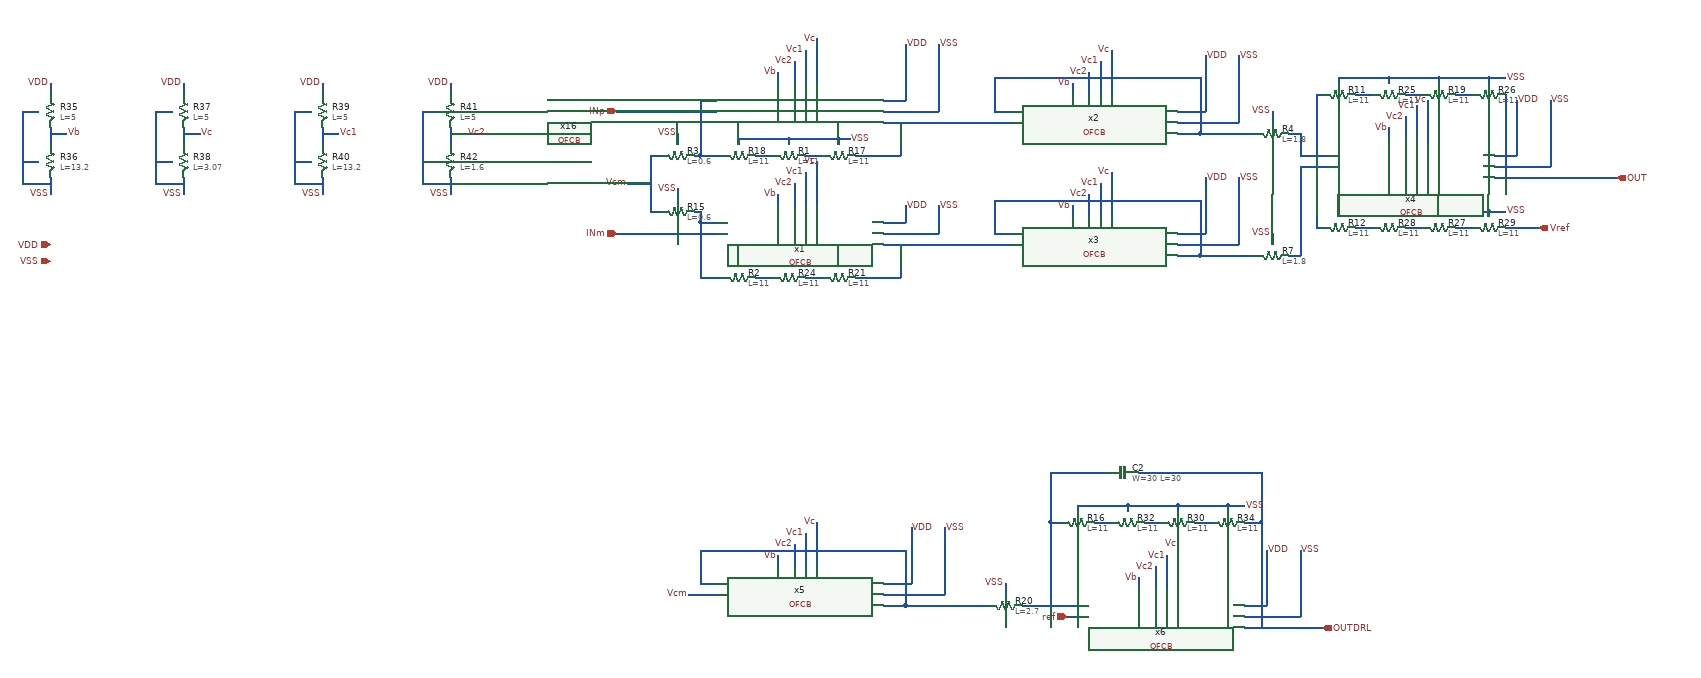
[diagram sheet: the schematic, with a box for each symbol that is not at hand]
v {xschem version=3.4.5 file_version=1.2
}
G {}
K {}
V {}
S {}
E {}
N -280 -930 -200 -930 {
lab=#net1}
N -280 -710 -200 -710 {
lab=#net2}
N 480 -850 520 -850 {
lab=#net3}
N 480 -870 520 -870 {
lab=#net4}
N -280 -970 -240 -970 {
lab=VDD}
N -240 -1070 -240 -970 {
lab=VDD}
N -280 -950 -200 -950 {
lab=VSS}
N -200 -950 -180 -950 {
lab=VSS}
N -180 -1070 -180 -950 {
lab=VSS}
N -280 -750 -240 -750 {
lab=VDD}
N -240 -780 -240 -750 {
lab=VDD}
N -280 -730 -180 -730 {
lab=VSS}
N -180 -780 -180 -730 {
lab=VSS}
N -680 -950 -580 -950 {
lab=INp}
N -680 -730 -580 -730 {
lab=INm}
N -610 -970 -580 -970 {
lab=#net5}
N -610 -970 -610 -910 {
lab=#net5}
N -250 -930 -250 -910 {
lab=#net1}
N -610 -750 -580 -750 {
lab=#net6}
N -610 -750 -610 -700 {
lab=#net6}
N -610 -700 -610 -690 {
lab=#net6}
N 820 -870 860 -870 {
lab=VDD}
N 860 -970 860 -870 {
lab=VDD}
N 820 -850 900 -850 {
lab=VSS}
N 900 -850 920 -850 {
lab=VSS}
N 920 -970 920 -850 {
lab=VSS}
N 820 -830 960 -830 {
lab=OUT}
N -250 -910 -250 -890 {
lab=#net1}
N -250 -710 -250 -690 {
lab=#net2}
N -250 -690 -250 -670 {
lab=#net2}
N 960 -830 1010 -830 {
lab=OUT}
N 1010 -830 1040 -830 {
lab=OUT}
N -610 -910 -610 -890 {
lab=#net5}
N -610 -690 -610 -670 {
lab=#net6}
N -200 -930 -190 -930 {
lab=#net1}
N -200 -710 -190 -710 {
lab=#net2}
N 500 -850 500 -740 {
lab=#net3}
N 500 -980 500 -870 {
lab=#net4}
N 840 -980 840 -830 {
lab=OUT}
N -190 -930 -50 -930 {
lab=#net1}
N -190 -710 -50 -710 {
lab=#net2}
N -80 -950 -50 -950 {
lab=#net7}
N -80 -1000 -80 -950 {
lab=#net7}
N -80 -1010 290 -1010 {
lab=#net7}
N 290 -1000 290 -910 {
lab=#net7}
N 250 -910 290 -910 {
lab=#net7}
N -80 -730 -50 -730 {
lab=#net8}
N -80 -780 -80 -730 {
lab=#net8}
N -80 -790 290 -790 {
lab=#net8}
N 290 -780 290 -690 {
lab=#net8}
N 250 -690 290 -690 {
lab=#net8}
N 260 -950 300 -950 {
lab=VDD}
N 300 -1050 300 -950 {
lab=VDD}
N 260 -930 340 -930 {
lab=VSS}
N 340 -930 360 -930 {
lab=VSS}
N 360 -1050 360 -930 {
lab=VSS}
N 250 -950 260 -950 {
lab=VDD}
N 250 -930 260 -930 {
lab=VSS}
N 260 -730 300 -730 {
lab=VDD}
N 300 -830 300 -730 {
lab=VDD}
N 260 -710 340 -710 {
lab=VSS}
N 340 -710 360 -710 {
lab=VSS}
N 360 -830 360 -710 {
lab=VSS}
N 250 -730 260 -730 {
lab=VDD}
N 250 -710 260 -710 {
lab=VSS}
N 470 -910 470 -870 {
lab=#net4}
N 470 -870 480 -870 {
lab=#net4}
N 470 -850 480 -850 {
lab=#net3}
N 470 -850 470 -690 {
lab=#net3}
N 290 -910 390 -910 {
lab=#net7}
N 450 -910 470 -910 {
lab=#net4}
N 450 -690 470 -690 {
lab=#net3}
N 290 -690 390 -690 {
lab=#net8}
N -250 -890 -250 -870 {
lab=#net1}
N -250 -670 -250 -650 {
lab=#net2}
N -610 -770 -610 -750 {
lab=#net6}
N -620 -770 -610 -770 {
lab=#net6}
N -620 -870 -610 -870 {
lab=#net5}
N -610 -890 -610 -870 {
lab=#net5}
N -700 -870 -680 -870 {
lab=Vcm}
N -700 -870 -700 -770 {
lab=Vcm}
N -700 -770 -680 -770 {
lab=Vcm}
N -760 -950 -680 -950 {
lab=INp}
N -760 -730 -680 -730 {
lab=INm}
N -740 -820 -700 -820 {
lab=Vcm}
N 370 -60 410 -60 {
lab=VDD}
N 410 -160 410 -60 {
lab=VDD}
N 370 -40 450 -40 {
lab=GND}
N 450 -40 470 -40 {
lab=GND}
N 470 -160 470 -40 {
lab=GND}
N 370 -20 510 -20 {
lab=OUTDRL}
N 400 -150 400 -20 {
lab=OUTDRL}
N 50 -40 70 -40 {
lab=ref}
N -30 -60 70 -60 {
lab=#net9}
N 20 -150 20 -60 {
lab=#net9}
N -140 -60 -90 -60 {
lab=#net10}
N 400 -210 400 -150 {
lab=OUTDRL}
N 20 -210 20 -150 {
lab=#net9}
N -610 -100 -580 -100 {
lab=#net10}
N -610 -150 -610 -100 {
lab=#net10}
N -610 -160 -240 -160 {
lab=#net10}
N -240 -150 -240 -60 {
lab=#net10}
N -280 -60 -240 -60 {
lab=#net10}
N -270 -100 -230 -100 {
lab=VDD}
N -230 -200 -230 -100 {
lab=VDD}
N -270 -80 -190 -80 {
lab=VSS}
N -190 -80 -170 -80 {
lab=VSS}
N -170 -200 -170 -80 {
lab=VSS}
N -280 -100 -270 -100 {
lab=VDD}
N -280 -80 -270 -80 {
lab=VSS}
N -240 -60 -140 -60 {
lab=#net10}
N -630 -80 -580 -80 {
lab=Vcm}
N -650 -910 -650 -890 {
lab=VSS}
N -650 -810 -650 -790 {
lab=VSS}
N -60 -100 -60 -80 {
lab=VSS}
N -610 -870 -570 -870 {
lab=#net5}
N -510 -870 -480 -870 {
lab=#net11}
N -420 -870 -390 -870 {
lab=#net12}
N -330 -870 -250 -870 {
lab=#net1}
N -540 -900 -540 -890 {
lab=VSS}
N -540 -900 -450 -900 {
lab=VSS}
N -450 -900 -450 -890 {
lab=VSS}
N -450 -900 -450 -890 {
lab=VSS}
N -450 -900 -360 -900 {
lab=VSS}
N -360 -900 -360 -890 {
lab=VSS}
N -360 -900 -340 -900 {
lab=VSS}
N -610 -650 -570 -650 {
lab=#net6}
N -510 -650 -480 -650 {
lab=#net13}
N -420 -650 -390 -650 {
lab=#net14}
N -330 -650 -250 -650 {
lab=#net2}
N -540 -680 -540 -670 {
lab=VSS}
N -540 -680 -450 -680 {
lab=VSS}
N -450 -680 -450 -670 {
lab=VSS}
N -450 -680 -450 -670 {
lab=VSS}
N -450 -680 -360 -680 {
lab=VSS}
N -360 -680 -360 -670 {
lab=VSS}
N -360 -680 -340 -680 {
lab=VSS}
N -610 -660 -610 -650 {
lab=#net6}
N -610 -670 -610 -660 {
lab=#net6}
N 420 -950 420 -930 {
lab=VSS}
N 420 -730 420 -710 {
lab=VSS}
N 570 -980 600 -980 {
lab=#net15}
N 660 -980 690 -980 {
lab=#net16}
N 540 -1010 540 -1000 {
lab=VSS}
N 540 -1010 630 -1010 {
lab=VSS}
N 630 -1010 630 -1000 {
lab=VSS}
N 630 -1010 630 -1000 {
lab=VSS}
N 630 -1010 720 -1010 {
lab=VSS}
N 720 -1010 720 -1000 {
lab=VSS}
N 720 -1010 740 -1010 {
lab=VSS}
N 500 -980 510 -980 {
lab=#net4}
N 750 -980 780 -980 {
lab=#net17}
N 810 -1010 810 -1000 {
lab=VSS}
N 740 -1010 810 -1010 {
lab=VSS}
N 810 -1010 840 -1010 {
lab=VSS}
N 570 -740 600 -740 {
lab=#net18}
N 660 -740 690 -740 {
lab=#net19}
N 540 -770 540 -760 {
lab=VSS}
N 540 -770 630 -770 {
lab=VSS}
N 630 -770 630 -760 {
lab=VSS}
N 630 -770 630 -760 {
lab=VSS}
N 630 -770 720 -770 {
lab=VSS}
N 720 -770 720 -760 {
lab=VSS}
N 720 -770 740 -770 {
lab=VSS}
N 500 -740 510 -740 {
lab=#net3}
N 750 -740 780 -740 {
lab=#net20}
N 810 -770 810 -760 {
lab=VSS}
N 740 -770 810 -770 {
lab=VSS}
N 810 -770 840 -770 {
lab=VSS}
N 840 -740 900 -740 {
lab=Vref}
N 100 -210 130 -210 {
lab=#net21}
N 190 -210 220 -210 {
lab=#net22}
N 70 -240 70 -230 {
lab=VSS}
N 70 -240 160 -240 {
lab=VSS}
N 160 -240 160 -230 {
lab=VSS}
N 160 -240 160 -230 {
lab=VSS}
N 160 -240 250 -240 {
lab=VSS}
N 250 -240 250 -230 {
lab=VSS}
N 250 -240 270 -240 {
lab=VSS}
N 30 -210 40 -210 {
lab=#net9}
N 280 -210 310 -210 {
lab=#net23}
N 340 -240 340 -230 {
lab=VSS}
N 270 -240 340 -240 {
lab=VSS}
N 340 -240 370 -240 {
lab=VSS}
N 370 -210 390 -210 {
lab=OUTDRL}
N 20 -210 30 -210 {
lab=#net9}
N -470 -1020 -470 -1000 {
lab=Vb}
N -440 -1040 -440 -1000 {
lab=Vc2}
N -420 -1060 -420 -1000 {
lab=Vc1}
N -400 -1080 -400 -1000 {
lab=Vc}
N -470 -800 -470 -780 {
lab=Vb}
N -440 -820 -440 -780 {
lab=Vc2}
N -420 -840 -420 -780 {
lab=Vc1}
N -400 -860 -400 -780 {
lab=Vc}
N 60 -780 60 -760 {
lab=Vb}
N 90 -800 90 -760 {
lab=Vc2}
N 110 -820 110 -760 {
lab=Vc1}
N 130 -840 130 -760 {
lab=Vc}
N -80 -790 -80 -780 {
lab=#net8}
N 290 -790 290 -780 {
lab=#net8}
N -80 -1010 -80 -1000 {
lab=#net7}
N 290 -1010 290 -1000 {
lab=#net7}
N 60 -1000 60 -980 {
lab=Vb}
N 90 -1020 90 -980 {
lab=Vc2}
N 110 -1040 110 -980 {
lab=Vc1}
N 130 -1060 130 -980 {
lab=Vc}
N 630 -920 630 -900 {
lab=Vb}
N 660 -940 660 -900 {
lab=Vc2}
N 680 -960 680 -900 {
lab=Vc1}
N 700 -970 700 -890 {
lab=Vc}
N -470 -150 -470 -130 {
lab=Vb}
N -440 -170 -440 -130 {
lab=Vc2}
N -420 -190 -420 -130 {
lab=Vc1}
N -400 -210 -400 -130 {
lab=Vc}
N -610 -160 -610 -150 {
lab=#net10}
N -240 -160 -240 -150 {
lab=#net10}
N 20 -300 20 -210 {
lab=#net9}
N 20 -300 120 -300 {
lab=#net9}
N 180 -300 390 -300 {
lab=OUTDRL}
N 400 -300 400 -210 {
lab=OUTDRL}
N 180 -110 180 -90 {
lab=Vb}
N 210 -130 210 -90 {
lab=Vc2}
N 230 -150 230 -90 {
lab=Vc1}
N 250 -170 250 -90 {
lab=Vc}
N 390 -210 400 -210 {
lab=OUTDRL}
N 390 -300 400 -300 {
lab=OUTDRL}
N -1780 -1000 -1780 -980 {
lab=VDD}
N -1780 -830 -1780 -800 {
lab=VSS}
N -1780 -920 -1780 -890 {
lab=Vb}
N -1780 -910 -1750 -910 {
lab=Vb}
N -1810 -950 -1800 -950 {
lab=VSS}
N -1830 -950 -1830 -820 {
lab=VSS}
N -1810 -820 -1780 -820 {
lab=VSS}
N -1810 -860 -1800 -860 {
lab=VSS}
N -1830 -950 -1810 -950 {
lab=VSS}
N -1830 -860 -1810 -860 {
lab=VSS}
N -1830 -820 -1810 -820 {
lab=VSS}
N -1540 -1000 -1540 -980 {
lab=VDD}
N -1540 -830 -1540 -800 {
lab=VSS}
N -1540 -920 -1540 -890 {
lab=Vc}
N -1540 -910 -1510 -910 {
lab=Vc}
N -1570 -950 -1560 -950 {
lab=VSS}
N -1590 -950 -1590 -820 {
lab=VSS}
N -1570 -820 -1540 -820 {
lab=VSS}
N -1570 -860 -1560 -860 {
lab=VSS}
N -1590 -950 -1570 -950 {
lab=VSS}
N -1590 -860 -1570 -860 {
lab=VSS}
N -1590 -820 -1570 -820 {
lab=VSS}
N -1290 -1000 -1290 -980 {
lab=VDD}
N -1290 -830 -1290 -800 {
lab=VSS}
N -1290 -920 -1290 -890 {
lab=Vc1}
N -1290 -910 -1260 -910 {
lab=Vc1}
N -1320 -950 -1310 -950 {
lab=VSS}
N -1340 -950 -1340 -820 {
lab=VSS}
N -1320 -820 -1290 -820 {
lab=VSS}
N -1320 -860 -1310 -860 {
lab=VSS}
N -1340 -950 -1320 -950 {
lab=VSS}
N -1340 -860 -1320 -860 {
lab=VSS}
N -1340 -820 -1320 -820 {
lab=VSS}
N -1060 -1000 -1060 -980 {
lab=VDD}
N -1060 -830 -1060 -800 {
lab=VSS}
N -1060 -920 -1060 -890 {
lab=Vc2}
N -1060 -910 -1030 -910 {
lab=Vc2}
N -1090 -950 -1080 -950 {
lab=VSS}
N -1110 -950 -1110 -820 {
lab=VSS}
N -1090 -820 -1060 -820 {
lab=VSS}
N -1090 -860 -1080 -860 {
lab=VSS}
N -1110 -950 -1090 -950 {
lab=VSS}
N -1110 -860 -1090 -860 {
lab=VSS}
N -1110 -820 -1090 -820 {
lab=VSS}
C {devices/lab_pin.sym} -740 -820 0 0 {name=p48 sig_type=std_logic lab=Vcm}
C {devices/lab_pin.sym} -630 -80 0 0 {name=p52 sig_type=std_logic lab=Vcm}
C {sky130_fd_pr/res_high_po_0p35.sym} -650 -870 1 0 {name=R3
L=0.6
model=res_high_po_0p35
spiceprefix=X
mult=1}
C {devices/lab_pin.sym} -650 -910 0 0 {name=p63 sig_type=std_logic lab=VSS}
C {sky130_fd_pr/res_high_po_0p35.sym} -650 -770 1 0 {name=R15
L=0.6
model=res_high_po_0p35
spiceprefix=X
mult=1}
C {devices/lab_pin.sym} -650 -810 0 0 {name=p64 sig_type=std_logic lab=VSS}
C {sky130_fd_pr/res_xhigh_po_0p35.sym} -540 -870 1 0 {name=R18
L=11
model=res_xhigh_po_0p35
spiceprefix=X
mult=1}
C {sky130_fd_pr/res_high_po_5p73.sym} -60 -60 1 0 {name=R20
L=2.7
model=res_high_po_5p73
spiceprefix=X
mult=1}
C {devices/lab_pin.sym} -60 -100 0 0 {name=p20 sig_type=std_logic lab=VSS}
C {sky130_fd_pr/res_xhigh_po_0p35.sym} -360 -870 1 0 {name=R17
L=11
model=res_xhigh_po_0p35
spiceprefix=X
mult=1}
C {sky130_fd_pr/res_xhigh_po_0p35.sym} -450 -870 1 0 {name=R1
L=11
model=res_xhigh_po_0p35
spiceprefix=X
mult=1}
C {devices/lab_pin.sym} -340 -900 0 1 {name=p21 sig_type=std_logic lab=VSS}
C {sky130_fd_pr/res_xhigh_po_0p35.sym} -540 -650 1 0 {name=R2
L=11
model=res_xhigh_po_0p35
spiceprefix=X
mult=1}
C {sky130_fd_pr/res_xhigh_po_0p35.sym} -360 -650 1 0 {name=R21
L=11
model=res_xhigh_po_0p35
spiceprefix=X
mult=1}
C {sky130_fd_pr/res_xhigh_po_0p35.sym} -450 -650 1 0 {name=R24
L=11
model=res_xhigh_po_0p35
spiceprefix=X
mult=1}
C {devices/lab_pin.sym} -340 -680 0 1 {name=p24 sig_type=std_logic lab=VSS}
C {sky130_fd_pr/res_xhigh_po_0p35.sym} 420 -910 1 0 {name=R4
L=1.8
model=res_xhigh_po_0p35
spiceprefix=X
mult=1}
C {sky130_fd_pr/res_xhigh_po_0p35.sym} 420 -690 1 0 {name=R7
L=1.8
model=res_xhigh_po_0p35
spiceprefix=X
mult=1}
C {devices/lab_pin.sym} 420 -950 0 0 {name=p26 sig_type=std_logic lab=VSS}
C {devices/lab_pin.sym} 420 -730 0 0 {name=p27 sig_type=std_logic lab=VSS}
C {sky130_fd_pr/res_xhigh_po_0p35.sym} 540 -980 1 0 {name=R11
L=11
model=res_xhigh_po_0p35
spiceprefix=X
mult=1}
C {sky130_fd_pr/res_xhigh_po_0p35.sym} 720 -980 1 0 {name=R19
L=11
model=res_xhigh_po_0p35
spiceprefix=X
mult=1}
C {sky130_fd_pr/res_xhigh_po_0p35.sym} 630 -980 1 0 {name=R25
L=11
model=res_xhigh_po_0p35
spiceprefix=X
mult=1}
C {devices/lab_pin.sym} 840 -1010 0 1 {name=p38 sig_type=std_logic lab=VSS}
C {sky130_fd_pr/res_xhigh_po_0p35.sym} 810 -980 1 0 {name=R26
L=11
model=res_xhigh_po_0p35
spiceprefix=X
mult=1}
C {sky130_fd_pr/res_xhigh_po_0p35.sym} 540 -740 1 0 {name=R12
L=11
model=res_xhigh_po_0p35
spiceprefix=X
mult=1}
C {sky130_fd_pr/res_xhigh_po_0p35.sym} 720 -740 1 0 {name=R27
L=11
model=res_xhigh_po_0p35
spiceprefix=X
mult=1}
C {sky130_fd_pr/res_xhigh_po_0p35.sym} 630 -740 1 0 {name=R28
L=11
model=res_xhigh_po_0p35
spiceprefix=X
mult=1}
C {devices/lab_pin.sym} 840 -770 0 1 {name=p40 sig_type=std_logic lab=VSS}
C {sky130_fd_pr/res_xhigh_po_0p35.sym} 810 -740 1 0 {name=R29
L=11
model=res_xhigh_po_0p35
spiceprefix=X
mult=1}
C {sky130_fd_pr/cap_mim_m3_1.sym} 150 -300 3 0 {name=C2 model=cap_mim_m3_1 W=30 L=30 MF=6 spiceprefix=X}
C {sky130_fd_pr/res_xhigh_po_0p35.sym} 70 -210 1 0 {name=R16
L=11
model=res_xhigh_po_0p35
spiceprefix=X
mult=1}
C {sky130_fd_pr/res_xhigh_po_0p35.sym} 250 -210 1 0 {name=R30
L=11
model=res_xhigh_po_0p35
spiceprefix=X
mult=1}
C {sky130_fd_pr/res_xhigh_po_0p35.sym} 160 -210 1 0 {name=R32
L=11
model=res_xhigh_po_0p35
spiceprefix=X
mult=1}
C {devices/lab_pin.sym} 370 -240 0 1 {name=p62 sig_type=std_logic lab=VSS}
C {sky130_fd_pr/res_xhigh_po_0p35.sym} 340 -210 1 0 {name=R34
L=11
model=res_xhigh_po_0p35
spiceprefix=X
mult=1}
C {OFCB.sym} -430 -910 0 0 {name=x16}
C {OFCB.sym} -430 -690 0 0 {name=x1}
C {OFCB.sym} 100 -890 0 0 {name=x2}
C {OFCB.sym} 100 -670 0 0 {name=x3}
C {OFCB.sym} 670 -810 0 0 {name=x4}
C {OFCB.sym} -430 -40 0 0 {name=x5}
C {OFCB.sym} 220 0 0 0 {name=x6}
C {devices/lab_pin.sym} -470 -1020 0 0 {name=p92 sig_type=std_logic lab=Vb}
C {devices/lab_pin.sym} -440 -1040 0 0 {name=p93 sig_type=std_logic lab=Vc2}
C {devices/lab_pin.sym} -420 -1060 0 0 {name=p94 sig_type=std_logic lab=Vc1}
C {devices/lab_pin.sym} -400 -1080 0 0 {name=p95 sig_type=std_logic lab=Vc}
C {devices/lab_pin.sym} -470 -800 0 0 {name=p96 sig_type=std_logic lab=Vb}
C {devices/lab_pin.sym} -440 -820 0 0 {name=p97 sig_type=std_logic lab=Vc2}
C {devices/lab_pin.sym} -420 -840 0 0 {name=p98 sig_type=std_logic lab=Vc1}
C {devices/lab_pin.sym} -400 -860 0 0 {name=p99 sig_type=std_logic lab=Vc}
C {devices/lab_pin.sym} 60 -780 0 0 {name=p100 sig_type=std_logic lab=Vb}
C {devices/lab_pin.sym} 90 -800 0 0 {name=p101 sig_type=std_logic lab=Vc2}
C {devices/lab_pin.sym} 110 -820 0 0 {name=p102 sig_type=std_logic lab=Vc1}
C {devices/lab_pin.sym} 130 -840 0 0 {name=p103 sig_type=std_logic lab=Vc}
C {devices/lab_pin.sym} 60 -1000 0 0 {name=p104 sig_type=std_logic lab=Vb}
C {devices/lab_pin.sym} 90 -1020 0 0 {name=p105 sig_type=std_logic lab=Vc2}
C {devices/lab_pin.sym} 110 -1040 0 0 {name=p106 sig_type=std_logic lab=Vc1}
C {devices/lab_pin.sym} 130 -1060 0 0 {name=p107 sig_type=std_logic lab=Vc}
C {devices/lab_pin.sym} 630 -920 0 0 {name=p108 sig_type=std_logic lab=Vb}
C {devices/lab_pin.sym} 660 -940 0 0 {name=p109 sig_type=std_logic lab=Vc2}
C {devices/lab_pin.sym} 680 -960 0 0 {name=p110 sig_type=std_logic lab=Vc1}
C {devices/lab_pin.sym} 700 -970 0 0 {name=p111 sig_type=std_logic lab=Vc}
C {devices/lab_pin.sym} -470 -150 0 0 {name=p112 sig_type=std_logic lab=Vb}
C {devices/lab_pin.sym} -440 -170 0 0 {name=p113 sig_type=std_logic lab=Vc2}
C {devices/lab_pin.sym} -420 -190 0 0 {name=p114 sig_type=std_logic lab=Vc1}
C {devices/lab_pin.sym} -400 -210 0 0 {name=p115 sig_type=std_logic lab=Vc}
C {devices/lab_pin.sym} 180 -110 0 0 {name=p116 sig_type=std_logic lab=Vb}
C {devices/lab_pin.sym} 210 -130 0 0 {name=p117 sig_type=std_logic lab=Vc2}
C {devices/lab_pin.sym} 230 -150 0 0 {name=p118 sig_type=std_logic lab=Vc1}
C {devices/lab_pin.sym} 250 -170 0 0 {name=p119 sig_type=std_logic lab=Vc}
C {devices/lab_wire.sym} -1780 -800 0 0 {name=p69 sig_type=std_logic lab=VSS}
C {devices/lab_wire.sym} -1780 -1000 0 0 {name=p73 sig_type=std_logic lab=VDD}
C {sky130_fd_pr/res_xhigh_po_0p35.sym} -1780 -950 0 0 {name=R35
L=5
model=res_xhigh_po_0p35
spiceprefix=X
mult=1}
C {sky130_fd_pr/res_xhigh_po_0p35.sym} -1780 -860 0 0 {name=R36
L=13.2
model=res_xhigh_po_0p35
spiceprefix=X
mult=1}
C {devices/lab_wire.sym} -1540 -800 0 0 {name=p80 sig_type=std_logic lab=VSS}
C {devices/lab_wire.sym} -1540 -1000 0 0 {name=p81 sig_type=std_logic lab=VDD}
C {sky130_fd_pr/res_xhigh_po_0p35.sym} -1540 -950 0 0 {name=R37
L=5
model=res_xhigh_po_0p35
spiceprefix=X
mult=1}
C {sky130_fd_pr/res_xhigh_po_0p35.sym} -1540 -860 0 0 {name=R38
L=3.07
model=res_xhigh_po_0p35
spiceprefix=X
mult=1}
C {devices/lab_wire.sym} -1290 -800 0 0 {name=p82 sig_type=std_logic lab=VSS}
C {devices/lab_wire.sym} -1290 -1000 0 0 {name=p83 sig_type=std_logic lab=VDD}
C {sky130_fd_pr/res_xhigh_po_0p35.sym} -1290 -950 0 0 {name=R39
L=5
model=res_xhigh_po_0p35
spiceprefix=X
mult=1}
C {sky130_fd_pr/res_xhigh_po_0p35.sym} -1290 -860 0 0 {name=R40
L=13.2
model=res_xhigh_po_0p35
spiceprefix=X
mult=1}
C {devices/lab_wire.sym} -1060 -800 0 0 {name=p86 sig_type=std_logic lab=VSS}
C {devices/lab_wire.sym} -1060 -1000 0 0 {name=p87 sig_type=std_logic lab=VDD}
C {sky130_fd_pr/res_xhigh_po_0p35.sym} -1060 -950 0 0 {name=R41
L=5
model=res_xhigh_po_0p35
spiceprefix=X
mult=1}
C {sky130_fd_pr/res_xhigh_po_0p35.sym} -1060 -860 0 0 {name=R42
L=1.6
model=res_xhigh_po_0p35
spiceprefix=X
mult=1}
C {devices/lab_pin.sym} -1750 -910 0 1 {name=p88 sig_type=std_logic lab=Vb}
C {devices/lab_pin.sym} -1510 -910 0 1 {name=p89 sig_type=std_logic lab=Vc}
C {devices/lab_pin.sym} -1260 -910 0 1 {name=p90 sig_type=std_logic lab=Vc1}
C {devices/lab_pin.sym} -1030 -910 0 1 {name=p91 sig_type=std_logic lab=Vc2}
C {devices/ipin.sym} -760 -950 0 0 {name=p1 lab=INp}
C {devices/ipin.sym} -760 -730 0 0 {name=p2 lab=INm}
C {devices/opin.sym} 1040 -830 0 0 {name=p3 lab=OUT}
C {devices/ipin.sym} 900 -740 0 1 {name=p4 lab=Vref}
C {devices/opin.sym} 510 -20 0 0 {name=p5 lab=OUTDRL}
C {devices/ipin.sym} 50 -40 0 0 {name=p6 lab=ref}
C {devices/lab_pin.sym} -240 -1070 0 1 {name=p7 sig_type=std_logic lab=VDD}
C {devices/lab_pin.sym} -180 -1070 0 1 {name=p8 sig_type=std_logic lab=VSS}
C {devices/lab_pin.sym} -240 -780 0 1 {name=p9 sig_type=std_logic lab=VDD}
C {devices/lab_pin.sym} 300 -1050 0 1 {name=p10 sig_type=std_logic lab=VDD}
C {devices/lab_pin.sym} 860 -970 0 1 {name=p11 sig_type=std_logic lab=VDD}
C {devices/lab_pin.sym} 300 -830 0 1 {name=p12 sig_type=std_logic lab=VDD}
C {devices/lab_pin.sym} -230 -200 0 1 {name=p13 sig_type=std_logic lab=VDD}
C {devices/lab_pin.sym} 410 -160 0 1 {name=p14 sig_type=std_logic lab=VDD}
C {devices/lab_pin.sym} -180 -780 0 1 {name=p15 sig_type=std_logic lab=VSS}
C {devices/lab_pin.sym} 360 -1050 0 1 {name=p16 sig_type=std_logic lab=VSS}
C {devices/lab_pin.sym} 920 -970 0 1 {name=p17 sig_type=std_logic lab=VSS}
C {devices/lab_pin.sym} 360 -830 0 1 {name=p22 sig_type=std_logic lab=VSS}
C {devices/lab_pin.sym} -170 -200 0 1 {name=p23 sig_type=std_logic lab=VSS}
C {devices/lab_pin.sym} 470 -160 0 1 {name=p25 sig_type=std_logic lab=VSS}
C {devices/iopin.sym} -1780 -710 0 0 {name=p28 lab=VDD}
C {devices/iopin.sym} -1780 -680 0 0 {name=p29 lab=VSS}
